VERSION 5.7 ;
  NOWIREEXTENSIONATPIN ON ;
  DIVIDERCHAR "/" ;
  BUSBITCHARS "[]" ;
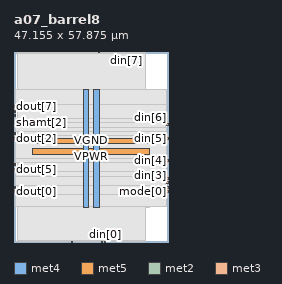
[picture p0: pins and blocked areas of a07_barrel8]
MACRO a07_barrel8
  CLASS BLOCK ;
  FOREIGN a07_barrel8 ;
  ORIGIN 0.000 0.000 ;
  SIZE 47.155 BY 57.875 ;
  PIN VGND
    DIRECTION INOUT ;
    USE GROUND ;
    PORT
      LAYER met4 ;
        RECT 24.340 10.640 25.940 46.480 ;
    END
    PORT
      LAYER met5 ;
        RECT 5.520 30.030 41.400 31.630 ;
    END
  END VGND
  PIN VPWR
    DIRECTION INOUT ;
    USE POWER ;
    PORT
      LAYER met4 ;
        RECT 21.040 10.640 22.640 46.480 ;
    END
    PORT
      LAYER met5 ;
        RECT 5.520 26.730 41.400 28.330 ;
    END
  END VPWR
  PIN din[0]
    DIRECTION INPUT ;
    USE SIGNAL ;
    ANTENNAGATEAREA 0.213000 ;
    PORT
      LAYER met2 ;
        RECT 27.690 0.000 27.970 0.280 ;
    END
  END din[0]
  PIN din[1]
    DIRECTION INPUT ;
    USE SIGNAL ;
    ANTENNAGATEAREA 0.213000 ;
    PORT
      LAYER met2 ;
        RECT 26.770 0.000 27.050 0.280 ;
    END
  END din[1]
  PIN din[2]
    DIRECTION INPUT ;
    USE SIGNAL ;
    ANTENNAGATEAREA 0.213000 ;
    PORT
      LAYER met3 ;
        RECT 46.555 16.360 47.155 16.960 ;
    END
  END din[2]
  PIN din[3]
    DIRECTION INPUT ;
    USE SIGNAL ;
    ANTENNAGATEAREA 0.213000 ;
    PORT
      LAYER met3 ;
        RECT 46.555 17.720 47.155 18.320 ;
    END
  END din[3]
  PIN din[4]
    DIRECTION INPUT ;
    USE SIGNAL ;
    ANTENNAGATEAREA 0.213000 ;
    PORT
      LAYER met3 ;
        RECT 46.555 24.520 47.155 25.120 ;
    END
  END din[4]
  PIN din[5]
    DIRECTION INPUT ;
    USE SIGNAL ;
    ANTENNAGATEAREA 0.213000 ;
    PORT
      LAYER met3 ;
        RECT 46.555 31.320 47.155 31.920 ;
    END
  END din[5]
  PIN din[6]
    DIRECTION INPUT ;
    USE SIGNAL ;
    ANTENNAGATEAREA 0.213000 ;
    PORT
      LAYER met3 ;
        RECT 46.555 35.400 47.155 36.000 ;
    END
  END din[6]
  PIN din[7]
    DIRECTION INPUT ;
    USE SIGNAL ;
    ANTENNAGATEAREA 0.213000 ;
    PORT
      LAYER met2 ;
        RECT 34.130 57.595 34.410 57.875 ;
    END
  END din[7]
  PIN dout[0]
    DIRECTION OUTPUT ;
    USE SIGNAL ;
    ANTENNADIFFAREA 0.702900 ;
    PORT
      LAYER met3 ;
        RECT 0.000 15.000 0.600 15.600 ;
    END
  END dout[0]
  PIN dout[1]
    DIRECTION OUTPUT ;
    USE SIGNAL ;
    ANTENNADIFFAREA 0.702900 ;
    PORT
      LAYER met3 ;
        RECT 0.000 23.160 0.600 23.760 ;
    END
  END dout[1]
  PIN dout[2]
    DIRECTION OUTPUT ;
    USE SIGNAL ;
    ANTENNADIFFAREA 0.702900 ;
    PORT
      LAYER met3 ;
        RECT 0.000 31.320 0.600 31.920 ;
    END
  END dout[2]
  PIN dout[3]
    DIRECTION OUTPUT ;
    USE SIGNAL ;
    ANTENNADIFFAREA 0.702900 ;
    PORT
      LAYER met3 ;
        RECT 0.000 39.480 0.600 40.080 ;
    END
  END dout[3]
  PIN dout[4]
    DIRECTION OUTPUT ;
    USE SIGNAL ;
    ANTENNADIFFAREA 0.702900 ;
    PORT
      LAYER met3 ;
        RECT 0.000 16.360 0.600 16.960 ;
    END
  END dout[4]
  PIN dout[5]
    DIRECTION OUTPUT ;
    USE SIGNAL ;
    ANTENNADIFFAREA 0.702900 ;
    PORT
      LAYER met3 ;
        RECT 0.000 21.800 0.600 22.400 ;
    END
  END dout[5]
  PIN dout[6]
    DIRECTION OUTPUT ;
    USE SIGNAL ;
    ANTENNADIFFAREA 0.702900 ;
    PORT
      LAYER met3 ;
        RECT 0.000 32.680 0.600 33.280 ;
    END
  END dout[6]
  PIN dout[7]
    DIRECTION OUTPUT ;
    USE SIGNAL ;
    ANTENNADIFFAREA 0.702900 ;
    PORT
      LAYER met3 ;
        RECT 0.000 40.840 0.600 41.440 ;
    END
  END dout[7]
  PIN mode[0]
    DIRECTION INPUT ;
    USE SIGNAL ;
    ANTENNAGATEAREA 0.213000 ;
    PORT
      LAYER met3 ;
        RECT 46.555 15.000 47.155 15.600 ;
    END
  END mode[0]
  PIN mode[1]
    DIRECTION INPUT ;
    USE SIGNAL ;
    ANTENNAGATEAREA 0.213000 ;
    PORT
      LAYER met2 ;
        RECT 25.850 57.595 26.130 57.875 ;
    END
  END mode[1]
  PIN shamt[0]
    DIRECTION INPUT ;
    USE SIGNAL ;
    ANTENNAGATEAREA 0.213000 ;
    PORT
      LAYER met3 ;
        RECT 46.555 19.080 47.155 19.680 ;
    END
  END shamt[0]
  PIN shamt[1]
    DIRECTION INPUT ;
    USE SIGNAL ;
    ANTENNAGATEAREA 0.213000 ;
    PORT
      LAYER met2 ;
        RECT 17.570 0.000 17.850 0.280 ;
    END
  END shamt[1]
  PIN shamt[2]
    DIRECTION INPUT ;
    USE SIGNAL ;
    ANTENNAGATEAREA 0.213000 ;
    PORT
      LAYER met3 ;
        RECT 0.000 38.120 0.600 38.720 ;
    END
  END shamt[2]
  OBS
      LAYER nwell ;
        RECT 5.330 10.795 41.590 46.430 ;
      LAYER li1 ;
        RECT 5.520 10.795 41.400 46.325 ;
      LAYER met1 ;
        RECT 0.990 10.640 41.400 46.480 ;
      LAYER met2 ;
        RECT 1.010 57.315 25.570 57.595 ;
        RECT 26.410 57.315 33.850 57.595 ;
        RECT 34.690 57.315 39.930 57.595 ;
        RECT 1.010 0.560 39.930 57.315 ;
        RECT 1.010 0.280 17.290 0.560 ;
        RECT 18.130 0.280 26.490 0.560 ;
        RECT 27.330 0.280 27.410 0.560 ;
        RECT 28.250 0.280 39.930 0.560 ;
      LAYER met3 ;
        RECT 0.600 41.840 46.555 46.405 ;
        RECT 1.000 37.720 46.555 41.840 ;
        RECT 0.600 36.400 46.555 37.720 ;
        RECT 0.600 35.000 46.155 36.400 ;
        RECT 0.600 33.680 46.555 35.000 ;
        RECT 1.000 32.320 46.555 33.680 ;
        RECT 1.000 30.920 46.155 32.320 ;
        RECT 0.600 25.520 46.555 30.920 ;
        RECT 0.600 24.160 46.155 25.520 ;
        RECT 1.000 24.120 46.155 24.160 ;
        RECT 1.000 21.400 46.555 24.120 ;
        RECT 0.600 20.080 46.555 21.400 ;
        RECT 0.600 17.360 46.155 20.080 ;
        RECT 1.000 14.600 46.155 17.360 ;
        RECT 0.600 10.715 46.555 14.600 ;
  END
END a07_barrel8
END LIBRARY

